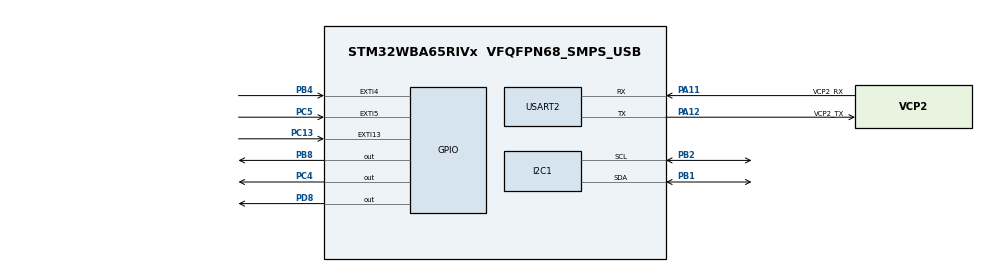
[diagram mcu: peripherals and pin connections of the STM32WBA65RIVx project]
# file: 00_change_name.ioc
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CORTEX_M33_NS.userName=CORTEX_M33
I2C1.Timing=0xA0101722
Mcu.Family=STM32WBA
Mcu.Name=STM32WBA65RIVx
Mcu.Package=VFQFPN68_SMPS_USB
NUCLEO-WBA65RI.BUTTON=1
NUCLEO-WBA65RI.BUTTON2=1
NUCLEO-WBA65RI.BUTTON3=1
NUCLEO-WBA65RI.LD1=true
NUCLEO-WBA65RI.LD2=true
NUCLEO-WBA65RI.LD3=true
NUCLEO-WBA65RI.VCP=false
NVIC.EXTI13_IRQn=true\:5\:0\:false\:false\:true\:true\:true\:true\:true
NVIC.EXTI4_IRQn=true\:5\:0\:false\:false\:true\:true\:true\:true\:true
NVIC.EXTI5_IRQn=true\:5\:0\:false\:false\:true\:true\:true\:true\:true
NVIC.PriorityGroup=NVIC_PRIORITYGROUP_4
NVIC.TIM1_UP_IRQn=true\:15\:0\:false\:false\:true\:false\:false\:true\:true
NVIC.TimeBase=TIM1_UP_IRQn
NVIC.TimeBaseIP=TIM1
OSC_IN.GPIO_Label=OSC_IN
OSC_IN.Mode=HSE-External-Clock-Source
OSC_IN.Signal=RCC_OSC_IN
OSC_OUT.GPIO_Label=OSC_OUT
OSC_OUT.Signal=RCC_OSC_OUT
PA11.GPIO_Label=VCP2_RX
PA11.GPIO_PuPd=GPIO_PULLUP
PA11.GPIO_Speed=GPIO_SPEED_FREQ_HIGH
PA11.Mode=Asynchronous
PA11.Signal=USART2_RX
PA12.GPIO_Label=VCP2_TX
PA12.GPIO_PuPd=GPIO_PULLUP
PA12.GPIO_Speed=GPIO_SPEED_FREQ_HIGH
PA12.Mode=Asynchronous
PA12.Signal=USART2_TX
PA13(JTMS/SWDIO).GPIO_Label=JTMS/SWDIO
PA13(JTMS/SWDIO).Signal=DEBUG_JTMS-SWDIO
PA14(JTCK/SWCLK).GPIO_Label=JTCLK/SWCLK
PA14(JTCK/SWCLK).Signal=DEBUG_JTCK-SWCLK
PA15(JTDI).GPIO_Label=VCP2_RTS
PA15(JTDI).GPIO_PuPd=GPIO_PULLUP
PA15(JTDI).GPIO_Speed=GPIO_SPEED_FREQ_HIGH
PA15(JTDI).Signal=USART2_RTS
PB1.Mode=I2C
PB1.Signal=I2C1_SDA
PB15.GPIO_Label=VCP2_CTS
PB15.GPIO_PuPd=GPIO_PULLUP
PB15.GPIO_Speed=GPIO_SPEED_FREQ_HIGH
PB15.Signal=USART2_CTS
PB2.Mode=I2C
PB2.Signal=I2C1_SCL
PB3(JTDO/TRACESWO).GPIO_Label=JTDO/SWO
PB3(JTDO/TRACESWO).Signal=DEBUG_JTDO-SWO
PB4(NJRST).Signal=GPXTI4
PB8.Signal=GPIO_Output
PC13.Signal=GPXTI13
PC14-OSC32_IN.GPIO_Label=OSC32_IN
PC14-OSC32_IN.Mode=LSE-External-Oscillator
PC14-OSC32_IN.Signal=RCC_OSC32_IN
PC15-OSC32_OUT.GPIO_Label=OSC32_OUT
PC15-OSC32_OUT.Mode=LSE-External-Oscillator
PC15-OSC32_OUT.Signal=RCC_OSC32_OUT
PC4.Signal=GPIO_Output
PC5.Signal=GPXTI5
PD6.GPIO_Label=USB_FS_P
PD6.Signal=USB_OTG_HS_DP
PD7.GPIO_Label=USB_FS_N
PD7.Signal=USB_OTG_HS_DM
PD8.Signal=GPIO_Output
ProjectManager.HeapSize=0x200
ProjectManager.StackSize=0x400
ProjectManager.TargetToolchain=STM32CubeIDE
RCC.ADCFreq_Value=66000000
RCC.AHB5CLKDivider=DIV4
RCC.AHBFreq_Value=66000000
RCC.APB1Freq_Value=66000000
RCC.APB1TimFreq_Value=66000000
RCC.APB2Freq_Value=66000000
RCC.APB2TimFreq_Value=66000000
RCC.CortexFreq_Value=8250000
RCC.HCLKFreq_Value=66000000
RCC.HSE_VALUE=32000000
RCC.HSI_VALUE=16000000
RCC.LSI1_VALUE=32000
RCC.LSI2_VALUE=32000
RCC.PLLFRACN=4096
RCC.PLLM=2
RCC.PLLN=16
RCC.SYSCLKFreq_VALUE=66000000
RCC.SYSCLKSourceVirtual=RCC_SYSCLKSOURCE_PLLCLK
RCC.VCOOutputFreq_Value=132000000
STMicroelectronics.X-CUBE-FREERTOS.1.3.1.RTOS2CcCMSISJjRTOS2JjCore=TZIiNonIiSupported
STMicroelectronics.X-CUBE-FREERTOS.1.3.1.RTOS2CcCMSISJjRTOS2JjHeap=HeapIi4
STMicroelectronics.X-CUBE-FREERTOS.1.3.1.configUSE_NEWLIB_REENTRANT=1
USART2.VirtualMode-Asynchronous=VM_ASYNC
VP_CORTEX_M33_NS_VS_Hclk.Mode=Hclk_Mode
VP_MEMORYMAP_VS_MEMORYMAP.Mode=CurAppReg
VP_NUCLEO-WBA65RI_VS_BSP_COMMON.Mode=COMMON
VP_PWR_VS_SECSignals.Mode=Security/Privilege
VP_RTC_VS_RTC_Activate.Mode=RTC_Enabled
VP_STMicroelectronics.X-CUBE-FREERTOS_VS_CMSISJjRTOS2_10.6.2_1.3.1.Mode=CMSISJjRTOS2
VP_SYS_VS_tim1.Mode=TIM1
board=NUCLEO-WBA65RI

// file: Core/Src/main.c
/* USER CODE BEGIN Header */
/**
  ******************************************************************************
  * @file           : main.c
  * @brief          : Main program body
  ******************************************************************************
  * @attention
  *
  * Copyright (c) 2025 STMicroelectronics.
  * All rights reserved.
  *
  * This software is licensed under terms that can be found in the LICENSE file
  * in the root directory of this software component.
  * If no LICENSE file comes with this software, it is provided AS-IS.
  *
  ******************************************************************************
  */
/* USER CODE END Header */
#include "main.h"
#include "cmsis_os2.h"

I2C_HandleTypeDef hi2c1;

RTC_HandleTypeDef hrtc;

UART_HandleTypeDef huart2;

/* Definitions for defaultTask */
osThreadId_t defaultTaskHandle;
const osThreadAttr_t defaultTask_attributes = {
  .name = "defaultTask",
  .priority = (osPriority_t) osPriorityNormal,
  .stack_size = 128 * 4
};
/* Definitions for LED_Task */
osThreadId_t LED_TaskHandle;
const osThreadAttr_t LED_Task_attributes = {
  .name = "LED_Task",
  .priority = (osPriority_t) osPriorityLow1,
  .stack_size = 128 * 4
};
/* Definitions for logger_task */
osThreadId_t logger_taskHandle;
const osThreadAttr_t logger_task_attributes = {
  .name = "logger_task",
  .priority = (osPriority_t) osPriorityLow,
  .stack_size = 128 * 4
};

void SystemClock_Config(void);
static void MX_GPIO_Init(void);
static void MX_I2C1_Init(void);
static void MX_RTC_Init(void);
static void MX_USART2_UART_Init(void);
void StartDefaultTask(void *argument);
void Led_t(void *argument);
void Logger_t(void *argument);

int main(void)
{

  /* MCU Configuration--------------------------------------------------------*/

  /* Reset of all peripherals, Initializes the Flash interface and the Systick. */
  HAL_Init();

  /* Configure the system clock */
  SystemClock_Config();

  /* Initialize all configured peripherals */
  MX_GPIO_Init();
  MX_I2C1_Init();
  MX_RTC_Init();
  MX_USART2_UART_Init();

  /* Init scheduler */
  osKernelInitialize();

  /* creation of defaultTask */
  defaultTaskHandle = osThreadNew(StartDefaultTask, NULL, &defaultTask_attributes);

  /* creation of LED_Task */
  LED_TaskHandle = osThreadNew(Led_t, NULL, &LED_Task_attributes);

  /* creation of logger_task */
  logger_taskHandle = osThreadNew(Logger_t, NULL, &logger_task_attributes);

  /* Initialize leds */
  BSP_LED_Init(LED_BLUE);
  BSP_LED_Init(LED_GREEN);
  BSP_LED_Init(LED_RED);

  /* Initialize USER push-button, will be used to trigger an interrupt each time it's pressed.*/
  BSP_PB_Init(B1, BUTTON_MODE_EXTI);
  BSP_PB_Init(B2, BUTTON_MODE_EXTI);
  BSP_PB_Init(B3, BUTTON_MODE_EXTI);

  /* Start scheduler */
  osKernelStart();

  /* Infinite loop */
  while (1)
  {

  }
}

void SystemClock_Config(void)
{
  RCC_OscInitTypeDef RCC_OscInitStruct = {0};
  RCC_ClkInitTypeDef RCC_ClkInitStruct = {0};

  /** Supply configuration update enable
  */
  HAL_PWREx_ConfigSupply(PWR_LDO_SUPPLY);

  /** Configure the main internal regulator output voltage
  */
  if (HAL_PWREx_ControlVoltageScaling(PWR_REGULATOR_VOLTAGE_SCALE1) != HAL_OK)
  {
    Error_Handler();
  }

  /** Initializes the CPU, AHB and APB busses clocks
  */
  RCC_OscInitStruct.OscillatorType = RCC_OSCILLATORTYPE_HSI|RCC_OSCILLATORTYPE_LSI;
  RCC_OscInitStruct.HSIState = RCC_HSI_ON;
  RCC_OscInitStruct.HSICalibrationValue = RCC_HSICALIBRATION_DEFAULT;
  RCC_OscInitStruct.LSIState = RCC_LSI1_ON;
  RCC_OscInitStruct.LSIDiv = RCC_LSI_DIV1;
  RCC_OscInitStruct.PLL1.PLLState = RCC_PLL_ON;
  RCC_OscInitStruct.PLL1.PLLSource = RCC_PLLSOURCE_HSI;
  RCC_OscInitStruct.PLL1.PLLM = 2;
  RCC_OscInitStruct.PLL1.PLLN = 16;
  RCC_OscInitStruct.PLL1.PLLP = 2;
  RCC_OscInitStruct.PLL1.PLLQ = 2;
  RCC_OscInitStruct.PLL1.PLLR = 2;
  RCC_OscInitStruct.PLL1.PLLFractional = 4096;
  if (HAL_RCC_OscConfig(&RCC_OscInitStruct) != HAL_OK)
  {
    Error_Handler();
  }

  /** Initializes the CPU, AHB and APB busses clocks
  */
  RCC_ClkInitStruct.ClockType = RCC_CLOCKTYPE_HCLK|RCC_CLOCKTYPE_SYSCLK
                              |RCC_CLOCKTYPE_PCLK1|RCC_CLOCKTYPE_PCLK2
                              |RCC_CLOCKTYPE_PCLK7|RCC_CLOCKTYPE_HCLK5;
  RCC_ClkInitStruct.SYSCLKSource = RCC_SYSCLKSOURCE_PLLCLK;
  RCC_ClkInitStruct.AHBCLKDivider = RCC_SYSCLK_DIV1;
  RCC_ClkInitStruct.APB1CLKDivider = RCC_HCLK_DIV1;
  RCC_ClkInitStruct.APB2CLKDivider = RCC_HCLK_DIV1;
  RCC_ClkInitStruct.APB7CLKDivider = RCC_HCLK_DIV1;
  RCC_ClkInitStruct.AHB5_PLL1_CLKDivider = RCC_SYSCLK_PLL1_DIV4;
  RCC_ClkInitStruct.AHB5_HSEHSI_CLKDivider = RCC_SYSCLK_HSEHSI_DIV1;

  if (HAL_RCC_ClockConfig(&RCC_ClkInitStruct, FLASH_LATENCY_2) != HAL_OK)
  {
    Error_Handler();
  }
}

static void MX_I2C1_Init(void)
{

  hi2c1.Instance = I2C1;
  hi2c1.Init.Timing = 0xA0101722;
  hi2c1.Init.OwnAddress1 = 0;
  hi2c1.Init.AddressingMode = I2C_ADDRESSINGMODE_7BIT;
  hi2c1.Init.DualAddressMode = I2C_DUALADDRESS_DISABLE;
  hi2c1.Init.OwnAddress2 = 0;
  hi2c1.Init.OwnAddress2Masks = I2C_OA2_NOMASK;
  hi2c1.Init.GeneralCallMode = I2C_GENERALCALL_DISABLE;
  hi2c1.Init.NoStretchMode = I2C_NOSTRETCH_DISABLE;
  if (HAL_I2C_Init(&hi2c1) != HAL_OK)
  {
    Error_Handler();
  }

  /** Configure Analogue filter
  */
  if (HAL_I2CEx_ConfigAnalogFilter(&hi2c1, I2C_ANALOGFILTER_ENABLE) != HAL_OK)
  {
    Error_Handler();
  }

  /** Configure Digital filter
  */
  if (HAL_I2CEx_ConfigDigitalFilter(&hi2c1, 0) != HAL_OK)
  {
    Error_Handler();
  }

}

static void MX_RTC_Init(void)
{

  RTC_PrivilegeStateTypeDef privilegeState = {0};

  /** Initialize RTC Only
  */
  hrtc.Instance = RTC;
  hrtc.Init.HourFormat = RTC_HOURFORMAT_24;
  hrtc.Init.AsynchPrediv = 127;
  hrtc.Init.SynchPrediv = 255;
  hrtc.Init.OutPut = RTC_OUTPUT_DISABLE;
  hrtc.Init.OutPutRemap = RTC_OUTPUT_REMAP_NONE;
  hrtc.Init.OutPutPolarity = RTC_OUTPUT_POLARITY_HIGH;
  hrtc.Init.OutPutType = RTC_OUTPUT_TYPE_OPENDRAIN;
  hrtc.Init.OutPutPullUp = RTC_OUTPUT_PULLUP_NONE;
  hrtc.Init.BinMode = RTC_BINARY_NONE;
  if (HAL_RTC_Init(&hrtc) != HAL_OK)
  {
    Error_Handler();
  }
  privilegeState.rtcPrivilegeFull = RTC_PRIVILEGE_FULL_NO;
  privilegeState.backupRegisterPrivZone = RTC_PRIVILEGE_BKUP_ZONE_NONE;
  privilegeState.backupRegisterStartZone2 = RTC_BKP_DR0;
  privilegeState.backupRegisterStartZone3 = RTC_BKP_DR0;
  if (HAL_RTCEx_PrivilegeModeSet(&hrtc, &privilegeState) != HAL_OK)
  {
    Error_Handler();
  }

}

static void MX_USART2_UART_Init(void)
{

  huart2.Instance = USART2;
  huart2.Init.BaudRate = 115200;
  huart2.Init.WordLength = UART_WORDLENGTH_8B;
  huart2.Init.StopBits = UART_STOPBITS_1;
  huart2.Init.Parity = UART_PARITY_NONE;
  huart2.Init.Mode = UART_MODE_TX_RX;
  huart2.Init.HwFlowCtl = UART_HWCONTROL_NONE;
  huart2.Init.OverSampling = UART_OVERSAMPLING_16;
  huart2.Init.OneBitSampling = UART_ONE_BIT_SAMPLE_DISABLE;
  huart2.Init.ClockPrescaler = UART_PRESCALER_DIV1;
  huart2.AdvancedInit.AdvFeatureInit = UART_ADVFEATURE_NO_INIT;
  if (HAL_UART_Init(&huart2) != HAL_OK)
  {
    Error_Handler();
  }
  if (HAL_UARTEx_SetTxFifoThreshold(&huart2, UART_TXFIFO_THRESHOLD_1_8) != HAL_OK)
  {
    Error_Handler();
  }
  if (HAL_UARTEx_SetRxFifoThreshold(&huart2, UART_RXFIFO_THRESHOLD_1_8) != HAL_OK)
  {
    Error_Handler();
  }
  if (HAL_UARTEx_DisableFifoMode(&huart2) != HAL_OK)
  {
    Error_Handler();
  }

}

static void MX_GPIO_Init(void)
{
  GPIO_InitTypeDef GPIO_InitStruct = {0};

  /* GPIO Ports Clock Enable */
  __HAL_RCC_GPIOD_CLK_ENABLE();
  __HAL_RCC_GPIOC_CLK_ENABLE();
  __HAL_RCC_GPIOB_CLK_ENABLE();
  __HAL_RCC_GPIOA_CLK_ENABLE();

  /*Configure GPIO pins : USB_FS_N_Pin USB_FS_P_Pin */
  GPIO_InitStruct.Pin = USB_FS_N_Pin|USB_FS_P_Pin;
  GPIO_InitStruct.Mode = GPIO_MODE_AF_PP;
  GPIO_InitStruct.Pull = GPIO_NOPULL;
  GPIO_InitStruct.Speed = GPIO_SPEED_FREQ_LOW;
  HAL_GPIO_Init(GPIOD, &GPIO_InitStruct);

}

void StartDefaultTask(void *argument)
{
  for(;;)
  {
    osDelay(1);
  }
}

void Led_t(void *argument)
{
  for(;;)
  {
    osDelay(1);
  }
}

void Logger_t(void *argument)
{
  for(;;)
  {
    osDelay(1);
  }
}

void HAL_TIM_PeriodElapsedCallback(TIM_HandleTypeDef *htim)
{
  if (htim->Instance == TIM1)
  {
    HAL_IncTick();
  }
}

void Error_Handler(void)
{
  __disable_irq();
  while (1)
  {
  }
}

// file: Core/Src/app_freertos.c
/* USER CODE BEGIN Header */
/**
  ******************************************************************************
  * File Name          : app_freertos.c
  * Description        : FreeRTOS applicative file
  ******************************************************************************
  * @attention
  *
  * Copyright (c) 2025 STMicroelectronics.
  * All rights reserved.
  *
  * This software is licensed under terms that can be found in the LICENSE file
  * in the root directory of this software component.
  * If no LICENSE file comes with this software, it is provided AS-IS.
  *
  ******************************************************************************
  */
/* USER CODE END Header */

#include "app_freertos.h"

/* Definitions for defaultTask */
osThreadId_t defaultTaskHandle;
const osThreadAttr_t defaultTask_attributes = {
  .name = "defaultTask",
  .priority = (osPriority_t) osPriorityNormal,
  .stack_size = 128 * 4
};
/* Definitions for LED_Task */
osThreadId_t LED_TaskHandle;
const osThreadAttr_t LED_Task_attributes = {
  .name = "LED_Task",
  .priority = (osPriority_t) osPriorityLow1,
  .stack_size = 128 * 4
};
/* Definitions for logger_task */
osThreadId_t logger_taskHandle;
const osThreadAttr_t logger_task_attributes = {
  .name = "logger_task",
  .priority = (osPriority_t) osPriorityLow,
  .stack_size = 128 * 4
};

void MX_FREERTOS_Init(void) {

  /* creation of defaultTask */
  defaultTaskHandle = osThreadNew(StartDefaultTask, NULL, &defaultTask_attributes);

  /* creation of LED_Task */
  LED_TaskHandle = osThreadNew(Led_t, NULL, &LED_Task_attributes);

  /* creation of logger_task */
  logger_taskHandle = osThreadNew(Logger_t, NULL, &logger_task_attributes);

}
void StartDefaultTask(void *argument)
{
  for(;;)
  {
    osDelay(1);
  }
}

void Led_t(void *argument)
{
  for(;;)
  {
    osDelay(1);
  }
}

void Logger_t(void *argument)
{
  for(;;)
  {
    osDelay(1);
  }
}
